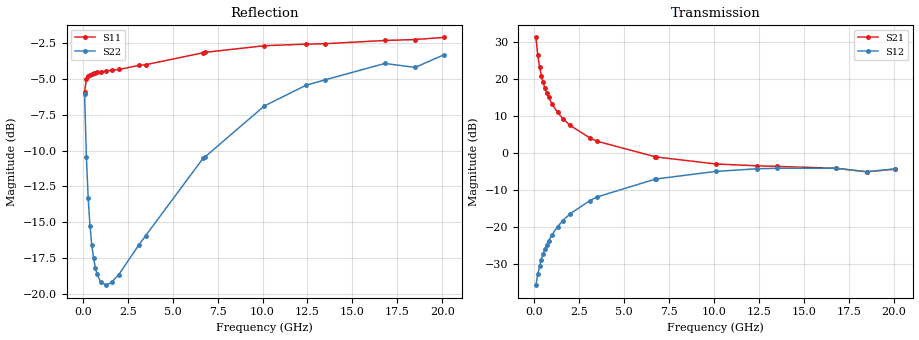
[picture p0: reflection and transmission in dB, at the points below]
!  Infineon Technologies AG
! BFR380L3 , PF131585-7, No.6, Th 09.10.01, soldered on pcb-board, measured with PP GSG850
!  Vce=2.5 V,  Ic=80.0 mA
! Common Emitter S-Parameters:  15. November 2001
#  GHz  S  MA  R  50
! f  S11  S21  S12  S22
! GHz  Mag  Ang  Mag  Ang  Mag  Ang  Mag  Ang
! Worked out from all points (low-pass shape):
!   201 points, 100 MHz to 20.1 GHz, reference 50 ohm
!   highest |S21| = 31.38 dB at 100 MHz (marker M1); lowest = -5.0 dB at 18.5 GHz (marker M2)
!   |S21| within 3 dB of the highest: start of sweep to 163.3 MHz
!   lowest |S11| = -5.9 dB at 100 MHz (marker M3), VSWR 3.04, Z = 20.5 - j23.2 ohm
!   |S11| at or under -10 dB: nowhere
!   |S22| runs from -19.4 to -3.3 dB; largest |S21 - S12| = 37
!   S11 on the Smith chart (normalised r, x): 100 MHz: 0.41, -0.46; 500 MHz: 0.26, -0.05; 3.1 GHz: 0.26, +0.35; 6.7 GHz: 0.30, +0.80; 12.4 GHz: 0.52, +1.53; 20.1 GHz: 1.05, +2.60
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0.1  0.5051 -123.7  37.06 124.9  0.0165 57.9  0.5006 -59.0
0.2  0.5613 -151.0  21.48 107.0  0.02304 57.1  0.2998 -80.4
0.3  0.5766 -162.6  14.85 99.2  0.02954 61.7  0.216 -91.6
0.4  0.5815 -169.3  11.29 94.3  0.03662 64.8  0.1732 -99.7
0.5  0.5852 -173.7  9.093 90.7  0.04367 67.2  0.1484 -106.1
0.6  0.5884 -177.4  7.611 87.9  0.05068 68.7  0.1333 -111.5
0.7  0.5902 179.6  6.553 85.3  0.05764 69.6  0.1234 -116.1
0.8  0.593 177.0  5.751 82.9  0.06508 70.2  0.117 -120.1
1  0.5957 172.4  4.629 78.9  0.07951 70.8  0.1098 -126.7
1.3  0.6002 166.8  3.592 73.3  0.1015 70.5  0.1073 -134.2
1.6  0.6027 161.5  2.946 68.2  0.1234 69.4  0.1098 -140.0
2  0.6072 155.2  2.39 61.9  0.1521 67.5  0.1167 -146.3
3.1  0.6271 139.6  1.619 46.4  0.2294 60.5  0.1476 -161.0
3.5  0.6309 134.1  1.459 41.2  0.2573 57.7  0.1597 -165.0
6.7  0.6947 99.3  0.9043 10.7  0.4451 34.2  0.2978 156.2
6.8  0.6969 98.1  0.8938 10.0  0.4508 33.4  0.3007 155.0
10.1  0.735 73.8  0.7183 -8.0  0.5698 10.6  0.4528 123.7
12.4  0.7444 62.2  0.679 -17.4  0.619 -3.9  0.5343 104.0
13.5  0.7471 57.2  0.6664 -22.0  0.6281 -10.4  0.5592 96.3
16.8  0.7667 45.8  0.6289 -32.9  0.6275 -26.1  0.6372 75.6
18.5  0.7726 44.2  0.5641 -40.0  0.5638 -34.4  0.6176 70.4
20.1  0.786 37.1  0.6105 -43.4  0.6177 -39.6  0.6837 59.7
